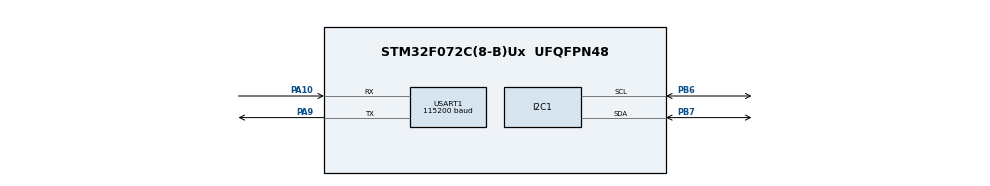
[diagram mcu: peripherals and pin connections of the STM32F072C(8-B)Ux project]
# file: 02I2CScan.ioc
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I2C1.Timing=0x20303E5D
Mcu.Family=STM32F0
Mcu.Name=STM32F072C(8-B)Ux
Mcu.Package=UFQFPN48
PA10.Mode=Asynchronous
PA10.Signal=USART1_RX
PA13.Mode=Serial_Wire
PA13.Signal=SYS_SWDIO
PA14.Mode=Serial_Wire
PA14.Signal=SYS_SWCLK
PA9.Mode=Asynchronous
PA9.Signal=USART1_TX
PB6.Mode=I2C
PB6.Signal=I2C1_SCL
PB7.Mode=I2C
PB7.Signal=I2C1_SDA
ProjectManager.HeapSize=0x200
ProjectManager.StackSize=0x400
ProjectManager.TargetToolchain=CMake
RCC.AHBFreq_Value=48000000
RCC.APB1Freq_Value=48000000
RCC.APB1TimFreq_Value=48000000
RCC.HCLKFreq_Value=48000000
RCC.I2c1ClockSelection=RCC_I2C1CLKSOURCE_SYSCLK
RCC.SYSCLKFreq_VALUE=48000000
RCC.SYSCLKSource=RCC_SYSCLKSOURCE_HSI48
USART1.BaudRate=115200
USART1.VirtualMode-Asynchronous=VM_ASYNC
board=custom

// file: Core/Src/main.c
/* USER CODE BEGIN Header */
/**
  ******************************************************************************
  * @file           : main.c
  * @brief          : Main program body
  ******************************************************************************
  * @attention
  *
  * Copyright (c) 2026 STMicroelectronics.
  * All rights reserved.
  *
  * This software is licensed under terms that can be found in the LICENSE file
  * in the root directory of this software component.
  * If no LICENSE file comes with this software, it is provided AS-IS.
  *
  ******************************************************************************
  */
/* USER CODE END Header */
#include "main.h"

/* USER CODE BEGIN Includes */
#include <stdio.h>
/*
 * I2C1 七位地址扫描：STM32F072CBU6，HSI 8 MHz。
 * PB6=SCL、PB7=SDA，二者为开漏输出，必须外接到 3.3 V 的上拉电阻；
 * USART1 PA9 以 115200 8N1 输出扫描结果。扫描 0x08..0x77 可避开保留地址。
 */
/* USER CODE END Includes */

I2C_HandleTypeDef hi2c1;

UART_HandleTypeDef huart1;

void SystemClock_Config(void);
static void MX_GPIO_Init(void);
static void MX_I2C1_Init(void);
static void MX_USART1_UART_Init(void);
/* USER CODE BEGIN PFP */
static void App_Init(void);
static void App_Loop(void);
/* USER CODE END PFP */

/* USER CODE BEGIN 0 */
/** @brief 通过 USART1 阻塞输出 printf 数据，最长等待 100 ms。 */
int _write(int file,char *ptr,int len){(void)file;if(ptr==NULL||len<=0)return 0;return HAL_UART_Transmit(&huart1,(uint8_t*)ptr,(uint16_t)len,100U)==HAL_OK?len:-1;}
/** @brief 外设已由 CubeMX 初始化，应用层无需额外启动。 */
static void App_Init(void){}
/*
 * 执行一轮扫描。HAL 接口使用左移一位后的地址格式，最低位留给读写位；
 * 每个地址尝试 2 次、单次超时 10 ms。NACK 只表示该地址无设备响应，
 * 不等同于程序错误；一轮结束后等待约 2 s 再扫描。
 */
static void App_Loop(void){uint32_t count=0;printf("\r\nI2C scan started\r\n");for(uint16_t a=0x08U;a<=0x77U;a++){if(HAL_I2C_IsDeviceReady(&hi2c1,(uint16_t)(a<<1),2U,10U)==HAL_OK){printf("Device found at 0x%02X\r\n",a);count++;}}printf("Scan complete, %lu device(s) found\r\n",(unsigned long)count);HAL_Delay(2000U);}
/* USER CODE END 0 */

int main(void)
{

  /* MCU Configuration--------------------------------------------------------*/

  /* Reset of all peripherals, Initializes the Flash interface and the Systick. */
  HAL_Init();

  /* Configure the system clock */
  SystemClock_Config();

  /* Initialize all configured peripherals */
  MX_GPIO_Init();
  MX_I2C1_Init();
  MX_USART1_UART_Init();
  /* USER CODE BEGIN 2 */
  App_Init();
  /* USER CODE END 2 */

  /* Infinite loop */
  /* USER CODE BEGIN WHILE */
  while (1)
  {
    App_Loop();
    /* USER CODE END WHILE */

  }
}

void SystemClock_Config(void)
{
  RCC_OscInitTypeDef RCC_OscInitStruct = {0};
  RCC_ClkInitTypeDef RCC_ClkInitStruct = {0};
  RCC_PeriphCLKInitTypeDef PeriphClkInit = {0};

  /** Initializes the RCC Oscillators according to the specified parameters
  * in the RCC_OscInitTypeDef structure.
  */
  RCC_OscInitStruct.OscillatorType = RCC_OSCILLATORTYPE_HSI;
  RCC_OscInitStruct.HSIState = RCC_HSI_ON;
  RCC_OscInitStruct.HSICalibrationValue = RCC_HSICALIBRATION_DEFAULT;
  RCC_OscInitStruct.PLL.PLLState = RCC_PLL_NONE;
  if (HAL_RCC_OscConfig(&RCC_OscInitStruct) != HAL_OK)
  {
    Error_Handler();
  }

  /** Initializes the CPU, AHB and APB buses clocks
  */
  RCC_ClkInitStruct.ClockType = RCC_CLOCKTYPE_HCLK|RCC_CLOCKTYPE_SYSCLK
                              |RCC_CLOCKTYPE_PCLK1;
  RCC_ClkInitStruct.SYSCLKSource = RCC_SYSCLKSOURCE_HSI;
  RCC_ClkInitStruct.AHBCLKDivider = RCC_SYSCLK_DIV1;
  RCC_ClkInitStruct.APB1CLKDivider = RCC_HCLK_DIV1;

  if (HAL_RCC_ClockConfig(&RCC_ClkInitStruct, FLASH_LATENCY_0) != HAL_OK)
  {
    Error_Handler();
  }
  PeriphClkInit.PeriphClockSelection = RCC_PERIPHCLK_USART1|RCC_PERIPHCLK_I2C1;
  PeriphClkInit.Usart1ClockSelection = RCC_USART1CLKSOURCE_PCLK1;
  PeriphClkInit.I2c1ClockSelection = RCC_I2C1CLKSOURCE_HSI;
  if (HAL_RCCEx_PeriphCLKConfig(&PeriphClkInit) != HAL_OK)
  {
    Error_Handler();
  }
}

static void MX_I2C1_Init(void)
{

  hi2c1.Instance = I2C1;
  hi2c1.Init.Timing = 0x2000090E;
  hi2c1.Init.OwnAddress1 = 0;
  hi2c1.Init.AddressingMode = I2C_ADDRESSINGMODE_7BIT;
  hi2c1.Init.DualAddressMode = I2C_DUALADDRESS_DISABLE;
  hi2c1.Init.OwnAddress2 = 0;
  hi2c1.Init.OwnAddress2Masks = I2C_OA2_NOMASK;
  hi2c1.Init.GeneralCallMode = I2C_GENERALCALL_DISABLE;
  hi2c1.Init.NoStretchMode = I2C_NOSTRETCH_DISABLE;
  if (HAL_I2C_Init(&hi2c1) != HAL_OK)
  {
    Error_Handler();
  }

  /** Configure Analogue filter
  */
  if (HAL_I2CEx_ConfigAnalogFilter(&hi2c1, I2C_ANALOGFILTER_ENABLE) != HAL_OK)
  {
    Error_Handler();
  }

  /** Configure Digital filter
  */
  if (HAL_I2CEx_ConfigDigitalFilter(&hi2c1, 0) != HAL_OK)
  {
    Error_Handler();
  }

}

static void MX_USART1_UART_Init(void)
{

  huart1.Instance = USART1;
  huart1.Init.BaudRate = 115200;
  huart1.Init.WordLength = UART_WORDLENGTH_8B;
  huart1.Init.StopBits = UART_STOPBITS_1;
  huart1.Init.Parity = UART_PARITY_NONE;
  huart1.Init.Mode = UART_MODE_TX_RX;
  huart1.Init.HwFlowCtl = UART_HWCONTROL_NONE;
  huart1.Init.OverSampling = UART_OVERSAMPLING_16;
  huart1.Init.OneBitSampling = UART_ONE_BIT_SAMPLE_DISABLE;
  huart1.AdvancedInit.AdvFeatureInit = UART_ADVFEATURE_NO_INIT;
  if (HAL_UART_Init(&huart1) != HAL_OK)
  {
    Error_Handler();
  }

}

static void MX_GPIO_Init(void)
{

  /* GPIO Ports Clock Enable */
  __HAL_RCC_GPIOA_CLK_ENABLE();
  __HAL_RCC_GPIOB_CLK_ENABLE();

}

void Error_Handler(void)
{
  __disable_irq();
  while (1)
  {
  }
}
